VERSION 5.8 ;
BUSBITCHARS "[]" ;
DIVIDERCHAR "/" ;

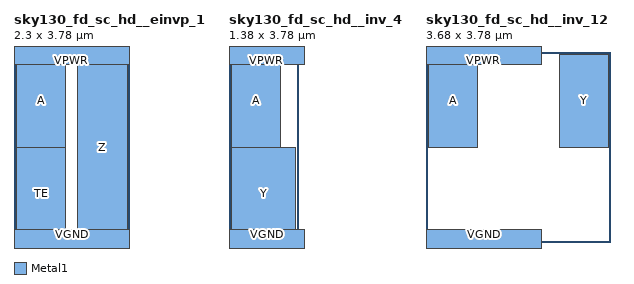
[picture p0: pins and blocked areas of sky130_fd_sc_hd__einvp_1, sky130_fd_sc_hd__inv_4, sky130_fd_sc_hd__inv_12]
MACRO sky130_fd_sc_hd__einvp_1
  CLASS CORE ;
  FOREIGN sky130_fd_sc_hd__einvp_1 ;
  ORIGIN 0 0 ;
  SIZE 2.3 BY 3.78 ;
  SYMMETRY X Y R90 ;
  SITE CoreSite ;
  PIN A
    DIRECTION INPUT ;  USE SIGNAL ;
    PORT  LAYER Metal1 ;  RECT 0.05 1.89 1.03 3.73 ;  END
  END A
  PIN TE
    DIRECTION INPUT ;  USE SIGNAL ;
    PORT  LAYER Metal1 ;  RECT 0.05 0.05 1.03 1.89 ;  END
  END TE
  PIN Z
    DIRECTION OUTPUT ;  USE SIGNAL ;
    PORT  LAYER Metal1 ;  RECT 1.26 0.05 2.25 3.73 ;  END
  END Z
  PIN VPWR
    DIRECTION INOUT ;  USE POWER ;  SHAPE ABUTMENT ;
    PORT  LAYER Metal1 ;  RECT 0 3.54 2.30 4.02 ;  END
  END VPWR
  PIN VGND
    DIRECTION INOUT ;  USE GROUND ;  SHAPE ABUTMENT ;
    PORT  LAYER Metal1 ;  RECT 0 -0.24 2.30 0.24 ;  END
  END VGND
END sky130_fd_sc_hd__einvp_1

MACRO sky130_fd_sc_hd__inv_4
  CLASS CORE ;
  FOREIGN sky130_fd_sc_hd__inv_4 ;
  ORIGIN 0 0 ;
  SIZE 1.38 BY 3.78 ;
  SYMMETRY X Y R90 ;
  SITE CoreSite ;
  PIN A
    DIRECTION INPUT ;  USE SIGNAL ;
    PORT  LAYER Metal1 ;  RECT 0.05 1.89 1.03 3.73 ;  END
  END A
  PIN Y
    DIRECTION OUTPUT ;  USE SIGNAL ;
    PORT  LAYER Metal1 ;  RECT 0.05 0.05 1.33 1.89 ;  END
  END Y
  PIN VPWR
    DIRECTION INOUT ;  USE POWER ;  SHAPE ABUTMENT ;
    PORT  LAYER Metal1 ;  RECT 0 3.54 2.30 4.02 ;  END
  END VPWR
  PIN VGND
    DIRECTION INOUT ;  USE GROUND ;  SHAPE ABUTMENT ;
    PORT  LAYER Metal1 ;  RECT 0 -0.24 2.30 0.24 ;  END
  END VGND
END sky130_fd_sc_hd__inv_4

MACRO sky130_fd_sc_hd__inv_12
  CLASS CORE ;
  FOREIGN sky130_fd_sc_hd__inv_12 ;
  ORIGIN 0 0 ;
  SIZE 3.68 BY 3.78 ;
  SYMMETRY X Y R90 ;
  SITE CoreSite ;
  PIN A
    DIRECTION INPUT ;  USE SIGNAL ;
    PORT  LAYER Metal1 ;  RECT 0.05 1.89 1.03 3.73 ;  END
  END A
  PIN Y
    DIRECTION OUTPUT ;  USE SIGNAL ;
    PORT  LAYER Metal1 ;  RECT 2.65 1.89 3.63 3.73 ;  END
  END Y
  PIN VPWR
    DIRECTION INOUT ;  USE POWER ;  SHAPE ABUTMENT ;
    PORT  LAYER Metal1 ;  RECT 0 3.54 2.30 4.02 ;  END
  END VPWR
  PIN VGND
    DIRECTION INOUT ;  USE GROUND ;  SHAPE ABUTMENT ;
    PORT  LAYER Metal1 ;  RECT 0 -0.24 2.30 0.24 ;  END
  END VGND
END sky130_fd_sc_hd__inv_12

END LIBRARY
